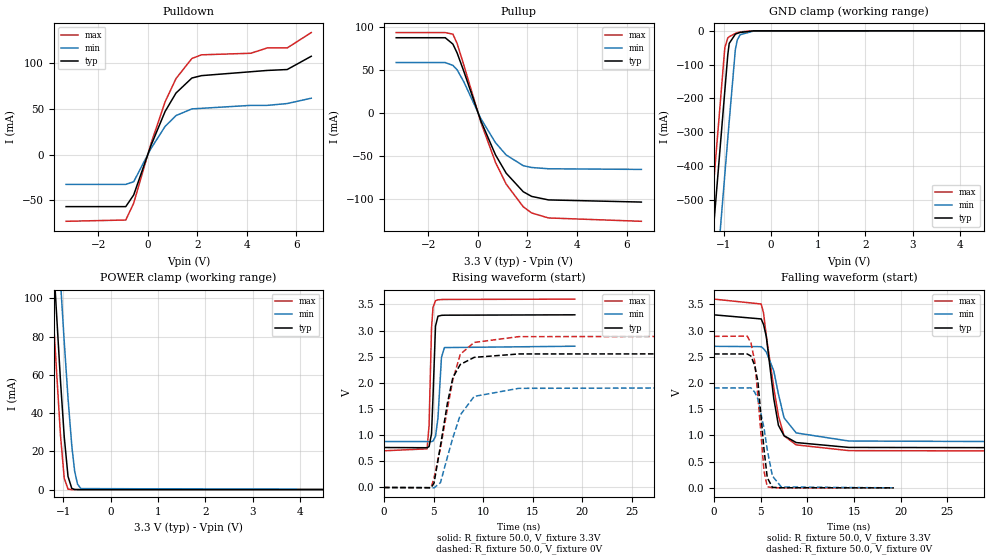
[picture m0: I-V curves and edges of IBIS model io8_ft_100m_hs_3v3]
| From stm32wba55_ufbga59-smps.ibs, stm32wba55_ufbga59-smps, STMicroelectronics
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[Model]   io8_ft_100m_hs_3v3
Model_type I/O
Polarity   Non-Inverting
Enable   Active-Low
| CAP_THRESHOLD on pad IOFT is "UDTCAPC" :
| Rising=30.0% of vddiom   Falling=70.0% of vddiom
| C_comp min and max val. don't necessarily correlate with the min and max pvt
| but are the smallest and greatest pad capacitance found.
| var   typ   min   max
C_comp   2.69710pF  2.55491pF  2.73102pF
|C_comp_pullup   1.75317pF  1.65278pF  1.79178pF
|C_comp_pulldown   943.93778fF  902.13346fF  939.24098fF
Vinl = 1.35V
Vinh = 1.8V
Vmeas = 1.65V   | Reference voltage for timing measurements
Cref  = 50.0pF   | Timing specification test load capacitance value
Rref  = 1.0MOhm   | Timing specification test load resistance value
Vref  = 1.815V   | Timing specification test load voltage
[Model Spec]
| TIME_THRESHOLD on pin ZIV11 is "CMOS" :
| Rising=50.0% of vdd   Falling=50.0% of vdd
Vinl 1.29050V 1.08150V 1.39050V
Vinh 1.79850V 1.49250V 1.94450V
| variable   typ   min   max
[Temperature Range] 25.0 140.0 -40.0
| variable   typ   min   max
[Voltage Range] 3.3V 2.7V 3.6V
| variable   typ   min   max
[POWER Clamp Reference] 3.3V 2.7V 3.6V
| variable   typ   min   max
[GND Clamp Reference] 0V 0V 0V
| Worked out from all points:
|   slope of the pulldown table from 0 to 0.495 V, typ, clamps not added: 14 ohm
|   slope of the pullup table from 0 to 0.495 V, typ, clamps not added: 13.8 ohm
|   GND clamp passes 1 mA (typ) near -0.51 V on its own axis
|   POWER clamp passes 1 mA (typ) near -0.83 V on its own axis
|   rising waveform, R_fixture 50.0, V_fixture 3.3V: 20-80 % time 250ps typ, 324ps min, 231ps max; typ from 0.764 V to 3.3 V
|   falling waveform, R_fixture 50.0, V_fixture 3.3V: 20-80 % time 1.12ns typ, 1.53ns min, 1.48ns max; typ from 3.3 V to 0.764 V
|   rising waveform, R_fixture 50.0, V_fixture 0V: 20-80 % time 1.41ns typ, 1.91ns min, 1.73ns max; typ from 0 V to 2.55 V
|   falling waveform, R_fixture 50.0, V_fixture 0V: 20-80 % time 784ps typ, 1.05ns min, 788ps max; typ from 2.55 V to 0 V
[POWER Clamp]
-3.3V     1.123A     1.139A     1.091A
-1.36V    189.2mA    238.8mA    158.1mA
-1.25V    139mA      190.3mA    108.1mA
-1.18V    107.9mA    159.9mA    77.22mA
-1.06V    57.23mA    109.3mA    28.68mA
-980mV    27.6mA     77.28mA    5.935mA
-900mV    6.895mA    47.74mA    242.8uA
-820mV    594.6uA    22.85mA    5.912uA
-760mV    69.41uA    9.714mA    358.6nA
-700mV    7.83uA     2.919mA    21.86nA
-630mV    611.5nA    529.9uA    954.5pA
6.6V      0A         0A         0A
[GND Clamp]
-3.3V     -4.134A    -4.382A    -4.006A
-1.59V    -1.227A    -1.475A    -1.099A
-1.25V    -648.9mA   -896.7mA   -520.9mA
-980mV    -189.9mA   -437.7mA   -61.92mA
-970mV    -172.9mA   -420.7mA   -48.45mA
-910mV    -70.86mA   -318.7mA   -21.03mA
-880mV    -37.23mA   -267.7mA   -17.31mA
-750mV    -9.908mA   -55.25mA   -7.768mA
-710mV    -7.626mA   -27.41mA   -5.608mA
-650mV    -4.885mA   -11.6mA    -3.058mA
-360mV    -31.22uA   -443.6uA   -1.188uA
6.6V      2.31nA     2.655uA    974.6pA
| variable   typ   min   max
[Pullup Reference] 3.3V 2.7V 3.6V
| variable   typ   min   max
[Pulldown Reference] 0V 0V 0V
[Pullup]
-3.3V     87.39mA    58.48mA    93.39mA
-1.32V    87.39mA    58.48mA    93.39mA
-1.01V    79.92mA    55.15mA    91.54mA
-840mV    69.62mA    50.05mA    80.64mA
-570mV    48.3mA     36.02mA    55.62mA
120mV     -9.566mA   -6.929mA   -11.25mA
710mV     -49.08mA   -34.92mA   -57.81mA
1.14V     -70.33mA   -49.14mA   -83.06mA
1.83V     -91.98mA   -61.62mA   -109.5mA
2.17V     -97.42mA   -63.75mA   -116.7mA
2.85V     -101.5mA   -65.23mA   -122.5mA
6.6V      -104mA     -65.97mA   -126.4mA
[Pulldown]
-3.3V     -56.7mA    -32.4mA    -72.73mA
-890mV    -56.7mA    -32.4mA    -71.32mA
-570mV    -43.94mA   -29.54mA   -52.99mA
120mV     9.474mA    6.407mA    11.48mA
700mV     47.33mA    30.97mA    57.88mA
1.14V     67.41mA    42.74mA    83.2mA
1.78V     83.75mA    50.04mA    105.1mA
2.17V     86.37mA    50.65mA    109.1mA
4.16V     90.61mA    53.89mA    110.8mA
4.82V     92.03mA    53.89mA    116.6mA
5.63V     93.04mA    55.89mA    116.6mA
6.6V      107.5mA    61.71mA    133.4mA
[Ramp]
dV/dt_r 1.53259V/1.41086ns 1.14345V/1.91029ns 1.73411V/1.72763ns
dV/dt_f 1.52157V/1.12298ns 1.09314V/1.46189ns 1.73924V/1.47498ns
R_load = 50.0
| Removed startup time: 0s 0s 0s  .
| Removed end time: 19.25ns.
[Rising Waveform]
R_fixture   = 50.0
V_fixture   = 3.3V
V_fixture_min = 2.7V
V_fixture_max = 3.6V
0s        764mV      878.1mV    701.3mV
4.35ns    759.8mV    877.9mV    738.6mV
4.55ns    782.3mV    876.5mV    1.182V
4.8ns     1.027V     876.1mV    3.05V
4.95ns    1.742V     888.7mV    3.445V
5.2ns     3.085V     975.1mV    3.57V
5.45ns    3.274V     1.331V     3.587V
5.8ns     3.29V      2.485V     3.592V
6.1ns     3.293V     2.674V     3.594V
19.25ns   3.3V       2.7V       3.6V
| Removed startup time: 0s 0s 0s  .
| Removed end time: 39.25ns.
[Falling Waveform]
R_fixture   = 50.0
V_fixture   = 3.3V
V_fixture_min = 2.7V
V_fixture_max = 3.6V
0s        3.3V       2.7V       3.6V
5.05ns    3.222V     2.693V     3.507V
5.3ns     3.116V     2.654V     3.338V
5.6ns     2.882V     2.59V      2.892V
6.4ns     1.699V     2.23V      1.904V
6.9ns     1.192V     1.787V     1.371V
7.5ns     994.9mV    1.336V     990.9mV
8.8ns     864.2mV    1.048V     820mV
14.45ns   771.2mV    893.3mV    710.1mV
39.25ns   764mV      878.1mV    701.3mV
| Removed startup time: 0s 0s 0s  .
| Removed end time: 39.2ns.
[Rising Waveform]
R_fixture   = 50.0
V_fixture   = 0V
V_fixture_min = 0V
V_fixture_max = 0V
0s        20.8nV     574.2nV    32.98nV
4.75ns    -4.717mV   -3.512mV   -3.576mV
5.05ns    82.95mV    -7.08mV    179.1mV
5.7ns     798.2mV    93.11mV    754mV
6.4ns     1.611V     580.7mV    1.504V
6.95ns    2.101V     950.8mV    2.057V
7.7ns     2.351V     1.387V     2.547V
9.1ns     2.487V     1.741V     2.772V
13.6ns    2.552V     1.895V     2.883V
39.2ns    2.554V     1.906V     2.89V
| Removed startup time: 0s 0s 0s  .
| Removed end time: 19.25ns.
[Falling Waveform]
R_fixture   = 50.0
V_fixture   = 0V
V_fixture_min = 0V
V_fixture_max = 0V
0s        2.554V     1.906V     2.89V
3.55ns    2.554V     1.906V     2.894V
3.95ns    2.514V     1.908V     2.767V
4.35ns    2.337V     1.827V     2.42V
4.7ns     2.022V     1.696V     1.743V
5.35ns    736.1mV    1.142V     322.4mV
5.7ns     195.4mV    725.2mV    20.86mV
6.25ns    10.28mV    227.4mV    3.246mV
7.2ns     2.221mV    17.74mV    1.646mV
19.25ns   27.12uV    32.82uV    48.95uV
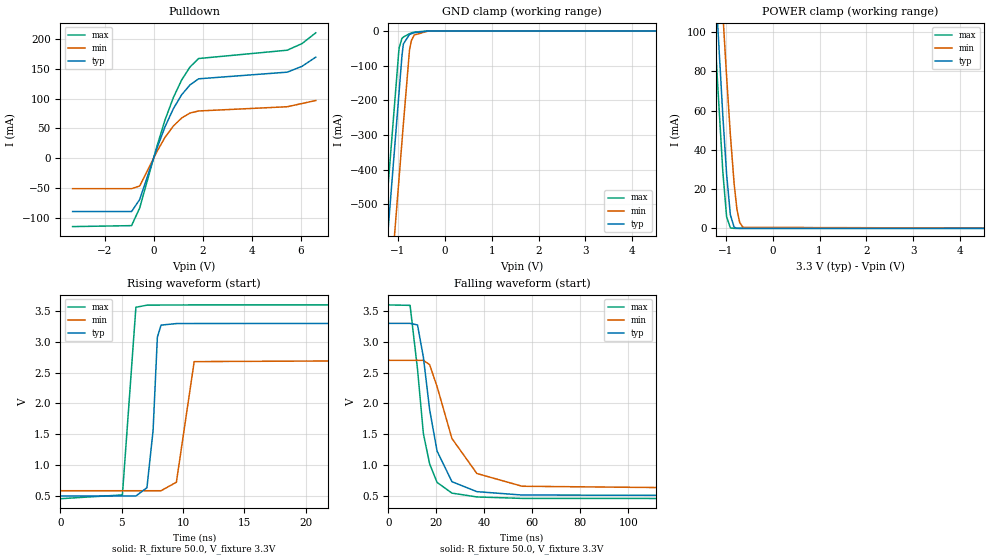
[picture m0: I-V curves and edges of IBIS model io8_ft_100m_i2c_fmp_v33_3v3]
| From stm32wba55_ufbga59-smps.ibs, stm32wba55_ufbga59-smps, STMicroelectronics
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[Model]   io8_ft_100m_i2c_fmp_v33_3v3
Model_type I/O_open_drain
Polarity   Non-Inverting
Enable   Active-Low
| CAP_THRESHOLD on pad IOFT is "UDTCAPC" :
| Rising=30.0% of vddiom   Falling=70.0% of vddiom
| C_comp min and max val. don't necessarily correlate with the min and max pvt
| but are the smallest and greatest pad capacitance found.
| var   typ   min   max
C_comp   2.70467pF  2.60096pF  2.73934pF
|C_comp_pulldown   2.70467pF  2.60096pF  2.73934pF
Vinl = 1.35V
Vinh = 1.8V
Vmeas = 1.65V   | Reference voltage for timing measurements
Cref  = 50.0pF   | Timing specification test load capacitance value
Rref  = 1.0MOhm   | Timing specification test load resistance value
Vref  = 1.815V   | Timing specification test load voltage
[Model Spec]
| TIME_THRESHOLD on pin ZII2CV11 is "CMOS" :
| Rising=50.0% of vdd   Falling=50.0% of vdd
Vinl 1.28450V 1.07650V 1.38450V
Vinh 1.79550V 1.49050V 1.94250V
| variable   typ   min   max
[Temperature Range] 25.0 140.0 -40.0
| variable   typ   min   max
[Voltage Range] 3.3V 2.7V 3.6V
| variable   typ   min   max
[POWER Clamp Reference] 3.3V 2.7V 3.6V
| variable   typ   min   max
[GND Clamp Reference] 0V 0V 0V
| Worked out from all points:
|   slope of the pulldown table from 0 to 0.495 V, typ, clamps not added: 8.84 ohm
|   GND clamp passes 1 mA (typ) near -0.51 V on its own axis
|   POWER clamp passes 1 mA (typ) near -0.83 V on its own axis
|   rising waveform, R_fixture 50.0, V_fixture 3.3V: 20-80 % time 550ps typ, 754ps min, 487ps max; typ from 0.496 V to 3.3 V
|   falling waveform, R_fixture 50.0, V_fixture 3.3V: 20-80 % time 7.24ns typ, 13.2ns min, 5.61ns max; typ from 3.3 V to 0.496 V
[POWER Clamp]
-3.3V     1.123A     1.139A     1.091A
-1.36V    189.2mA    238.8mA    158.1mA
-1.25V    139mA      190.3mA    108.1mA
-1.18V    107.9mA    159.9mA    77.22mA
-1.06V    57.23mA    109.3mA    28.68mA
-980mV    27.6mA     77.28mA    5.935mA
-900mV    6.895mA    47.74mA    242.8uA
-820mV    594.6uA    22.85mA    5.912uA
-760mV    69.41uA    9.714mA    358.6nA
-700mV    7.83uA     2.919mA    21.86nA
-630mV    611.5nA    529.9uA    954.5pA
6.6V      0A         0A         0A
[GND Clamp]
-3.3V     -4.134A    -4.382A    -4.006A
-1.59V    -1.227A    -1.475A    -1.099A
-1.25V    -648.9mA   -896.7mA   -520.9mA
-980mV    -189.9mA   -437.7mA   -61.92mA
-970mV    -172.9mA   -420.7mA   -48.45mA
-910mV    -70.86mA   -318.7mA   -21.03mA
-880mV    -37.23mA   -267.7mA   -17.31mA
-750mV    -9.908mA   -55.25mA   -7.768mA
-710mV    -7.626mA   -27.41mA   -5.608mA
-650mV    -4.885mA   -11.6mA    -3.058mA
-360mV    -31.22uA   -443.6uA   -1.188uA
6.6V      2.31nA     2.655uA    974.6pA
| variable   typ   min   max
[Pullup Reference] 3.3V 2.7V 3.6V
| variable   typ   min   max
[Pulldown Reference] 0V 0V 0V
[Pulldown]
-3.3V     -89.63mA   -51.21mA   -114.9mA
-900mV    -89.63mA   -51.21mA   -113.3mA
-570mV    -69.46mA   -46.7mA    -83.73mA
120mV     14.97mA    10.13mA    18.13mA
460mV     52.55mA    34.91mA    63.97mA
800mV     83.04mA    54mA       101.7mA
1.14V     106.6mA    67.57mA    131.5mA
1.48V     123.2mA    75.9mA     153.3mA
1.83V     133.4mA    79.37mA    167.5mA
5.44V     144.6mA    86.51mA    181.5mA
6.04V     154.4mA    91.91mA    192.6mA
6.6V      169.8mA    96.95mA    210.7mA
[Ramp]
dV/dt_r 1.68259V/549.39557ps 1.27116V/751.78769ps 1.88895V/488.49833ps
dV/dt_f 1.68262V/7.2351ns 1.27121V/13.13112ns 1.88896V/5.46778ns
R_load = 50.0
| Removed startup time: 0s 0s 0s  .
| Removed end time: 33.35ns.
[Rising Waveform]
R_fixture   = 50.0
V_fixture   = 3.3V
V_fixture_min = 2.7V
V_fixture_max = 3.6V
0s        495.6mV    581.3mV    451.7mV
5.05ns    495.6mV    581.3mV    512.9mV
6.15ns    495.6mV    581.3mV    3.562V
7.05ns    630.3mV    581.3mV    3.596V
7.55ns    1.56V      581.3mV    3.597V
7.9ns     3.077V     581.3mV    3.597V
8.2ns     3.272V     581.3mV    3.598V
9.45ns    3.297V     719.2mV    3.599V
10.9ns    3.298V     2.679V     3.6V
33.35ns   3.3V       2.7V       3.6V
| Removed startup time: 0s 0s 0s  .
| Removed end time: 248.4ns.
[Falling Waveform]
R_fixture   = 50.0
V_fixture   = 3.3V
V_fixture_min = 2.7V
V_fixture_max = 3.6V
0s        3.3V       2.7V       3.6V
9.05ns    3.3V       2.7V       3.593V
12.15ns   3.275V     2.7V       2.555V
14.6ns    2.75V      2.7V       1.508V
17.2ns    1.9V       2.629V     1.018V
20.3ns    1.226V     2.273V     716.5mV
26.5ns    728.3mV    1.429V     542.3mV
36.9ns    566.1mV    861.2mV    480.2mV
55.75ns   511.3mV    653.9mV    456.5mV
248.4ns   495.6mV    581.3mV    451.7mV
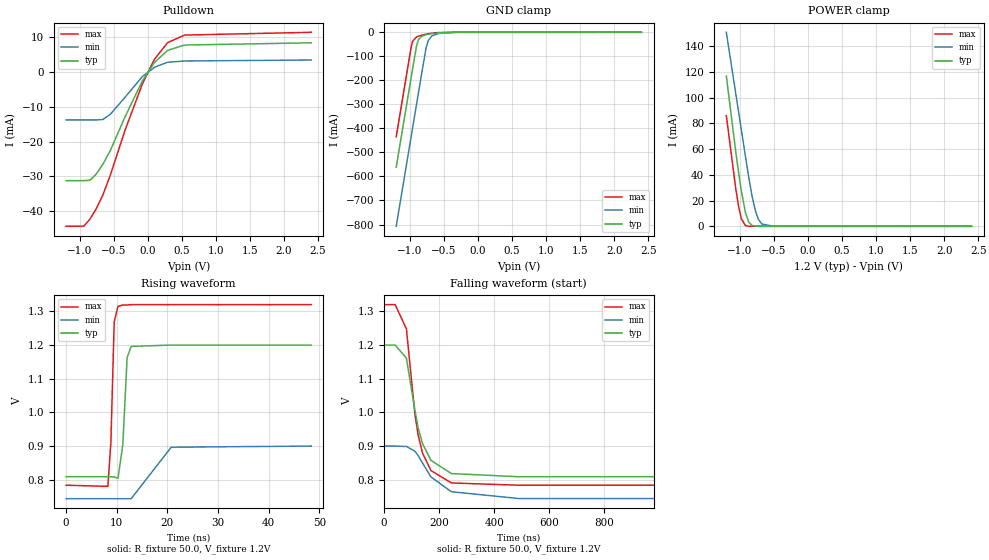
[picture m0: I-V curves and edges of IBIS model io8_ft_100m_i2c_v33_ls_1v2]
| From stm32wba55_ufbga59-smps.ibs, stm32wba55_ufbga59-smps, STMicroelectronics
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[Model]   io8_ft_100m_i2c_v33_ls_1v2
Model_type I/O_open_drain
Polarity   Non-Inverting
Enable   Active-Low
| CAP_THRESHOLD on pad IOFT is "UDTCAPC" :
| Rising=30.0% of vddiom   Falling=70.0% of vddiom
| C_comp min and max val. don't necessarily correlate with the min and max pvt
| but are the smallest and greatest pad capacitance found.
| var   typ   min   max
C_comp   1.75955pF  1.58205pF  1.89750pF
|C_comp_pulldown   1.75955pF  1.58205pF  1.89750pF
Vinl = 450.0mV
Vinh = 660.0mV
Vmeas = 600.0mV   | Reference voltage for timing measurements
Cref  = 50.0pF   | Timing specification test load capacitance value
Rref  = 1.0MOhm   | Timing specification test load resistance value
Vref  = 660.0mV   | Timing specification test load voltage
[Model Spec]
| TIME_THRESHOLD on pin ZII2CV11 is "CMOS" :
| Rising=50.0% of vdd   Falling=50.0% of vdd
Vinl 436.50000mV 342.50000mV 466.50000mV
Vinh 753.50000mV 549.50000mV 839.50000mV
| variable   typ   min   max
[Temperature Range] 25.0 140.0 -40.0
| variable   typ   min   max
[Voltage Range] 1.2V 900.0mV 1.32V
| variable   typ   min   max
[POWER Clamp Reference] 1.2V 900.0mV 1.32V
| variable   typ   min   max
[GND Clamp Reference] 0V 0V 0V
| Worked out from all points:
|   slope of the pulldown table from 0 to 0.18 V, typ, clamps not added: 40.6 ohm
|   GND clamp passes 1 mA (typ) near -0.51 V on its own axis
|   POWER clamp passes 1 mA (typ) near -0.83 V on its own axis
|   rising waveform, R_fixture 50.0, V_fixture 1.2V: 20-80 % time 743ps typ, 1.41ns min, 562ps max; typ from 0.809 V to 1.2 V
|   falling waveform, R_fixture 50.0, V_fixture 1.2V: 20-80 % time 59.4ns typ, 93.9ns min, 50.5ns max; typ from 1.2 V to 0.809 V
[POWER Clamp]
-1.2V     116.7mA    150.7mA    85.92mA
-1.06V    57.23mA    102.6mA    28.68mA
-1.02V    41.75mA    88.91mA    15.5mA
-980mV    27.6mA     75.18mA    5.935mA
-920mV    10.75mA    54.6mA     597.6uA
-870mV    3.065mA    37.68mA    60.82uA
-820mV    594.6uA    22.85mA    5.912uA
-770mV    99.71uA    11.47mA    572nA
-730mV    23.34uA    5.552mA    88.29nA
-680mV    3.779uA    1.833mA    8.565nA
-510mV    7.889nA    23.13uA    53.67pA
2.4V      0A         0A         0A
[GND Clamp]
-1.2V     -561.6mA   -807.5mA   -434.8mA
-980mV    -187.6mA   -433.5mA   -60.76mA
-960mV    -153.6mA   -399.5mA   -38.21mA
-900mV    -54.17mA   -297.5mA   -18.87mA
-870mV    -29.55mA   -246.5mA   -15.73mA
-830mV    -17.05mA   -178.5mA   -12.57mA
-760mV    -9.921mA   -62.77mA   -8.045mA
-730mV    -8.191mA   -35.56mA   -6.403mA
-680mV    -5.826mA   -15.57mA   -4.089mA
-580mV    -2.43mA    -5.043mA   -1.157mA
-330mV    -11.72uA   -245.5uA   -300.5nA
2.4V      872pA      1.056uA    338.3pA
| variable   typ   min   max
[Pullup Reference] 1.2V 900.0mV 1.32V
| variable   typ   min   max
[Pulldown Reference] 0V 0V 0V
[Pulldown]
-1.2V     -31.2mA    -13.81mA   -44.3mA
-940mV    -31.2mA    -13.81mA   -44.26mA
-850mV    -31.11mA   -13.81mA   -42.26mA
-760mV    -29.39mA   -13.81mA   -39.38mA
-660mV    -26.52mA   -13.68mA   -35.32mA
-550mV    -22.55mA   -12.17mA   -29.6mA
-330mV    -12.74mA   -7.204mA   -16.5mA
-80mV     -2.622mA   -1.37mA    -3.49mA
100mV     2.727mA    1.319mA    3.679mA
290mV     6.144mA    2.737mA    8.347mA
540mV     7.674mA    3.096mA    10.53mA
2.4V      8.312mA    3.389mA    11.33mA
[Ramp]
dV/dt_r 234.64946mV/730.32474ps 93.7375mV/1.38904ns 321.76547mV/556.33055ps
dV/dt_f 234.65958mV/57.74443ns 93.75738mV/89.13367ns 321.77283mV/49.68352ns
R_load = 50.0
| Removed startup time: 0s 0s 0s  .
| Removed end time: 48.4ns.
[Rising Waveform]
R_fixture   = 50.0
V_fixture   = 1.2V
V_fixture_min = 900.0mV
V_fixture_max = 1.32V
0s        808.9mV    743.7mV    783.7mV
8.25ns    808.9mV    743.7mV    780.3mV
8.85ns    808.9mV    743.7mV    912.1mV
9.5ns     808.4mV    743.7mV    1.269V
10.25ns   804.2mV    743.7mV    1.315V
11.2ns    903.5mV    743.7mV    1.319V
12.05ns   1.163V     743.7mV    1.319V
12.85ns   1.196V     743.7mV    1.32V
20.75ns   1.2V       896.6mV    1.32V
48.4ns    1.2V       900mV      1.32V
| Removed startup time: 0s 0s 0s  .
| Removed end time: 1.9984us.
[Falling Waveform]
R_fixture   = 50.0
V_fixture   = 1.2V
V_fixture_min = 900.0mV
V_fixture_max = 1.32V
0s        1.2V       900mV      1.32V
40.8ns    1.2V       900mV      1.32V
81.55ns   1.161V     898.8mV    1.248V
112.3ns   1.007V     884.6mV    994.5mV
124.5ns   952.6mV    871mV      931mV
140.3ns   906.8mV    849.2mV    878.6mV
170.6ns   857.5mV    808.3mV    827.2mV
244.7ns   818.3mV    764.3mV    790.4mV
489.4ns   808.9mV    744.2mV    783.7mV
1.998us   808.9mV    743.7mV    783.7mV
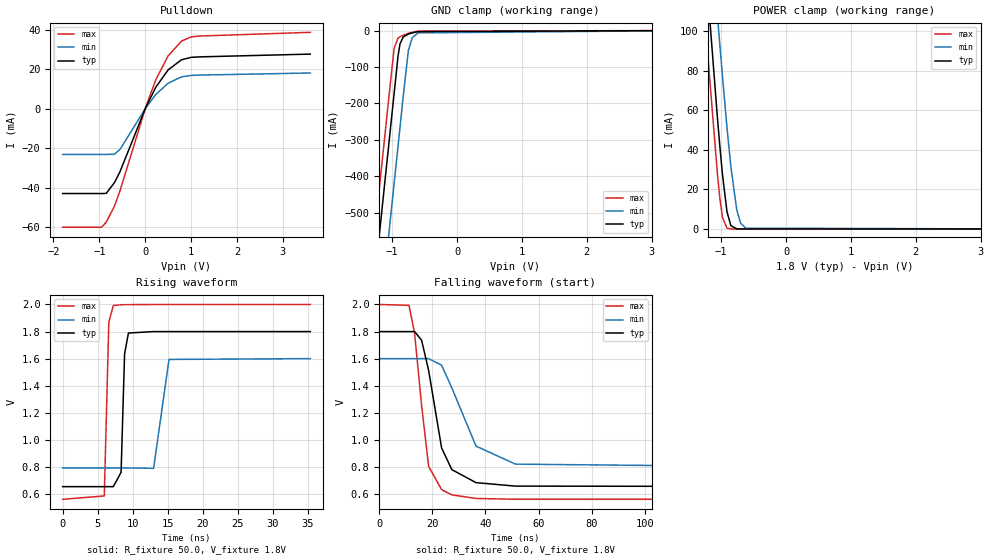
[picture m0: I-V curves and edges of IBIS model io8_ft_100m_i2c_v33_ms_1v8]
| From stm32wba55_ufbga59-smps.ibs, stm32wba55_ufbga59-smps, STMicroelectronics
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[Model]   io8_ft_100m_i2c_v33_ms_1v8
Model_type I/O_open_drain
Polarity   Non-Inverting
Enable   Active-Low
| CAP_THRESHOLD on pad IOFT is "UDTCAPC" :
| Rising=30.0% of vddiom   Falling=70.0% of vddiom
| C_comp min and max val. don't necessarily correlate with the min and max pvt
| but are the smallest and greatest pad capacitance found.
| var   typ   min   max
C_comp   2.22395pF  2.11500pF  2.41696pF
|C_comp_pulldown   2.22395pF  2.11500pF  2.41696pF
Vinl = 800.0mV
Vinh = 1.0V
Vmeas = 900.0mV   | Reference voltage for timing measurements
Cref  = 50.0pF   | Timing specification test load capacitance value
Rref  = 1.0MOhm   | Timing specification test load resistance value
Vref  = 990.0mV   | Timing specification test load voltage
[Model Spec]
| TIME_THRESHOLD on pin ZII2CV11 is "CMOS" :
| Rising=50.0% of vdd   Falling=50.0% of vdd
Vinl 697.50000mV 636.50000mV 765.50000mV
Vinh 1.08850V 942.50000mV 1.21750V
| variable   typ   min   max
[Temperature Range] 25.0 140.0 -40.0
| variable   typ   min   max
[Voltage Range] 1.8V 1.6V 2.0V
| variable   typ   min   max
[POWER Clamp Reference] 1.8V 1.6V 2.0V
| variable   typ   min   max
[GND Clamp Reference] 0V 0V 0V
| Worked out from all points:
|   slope of the pulldown table from 0 to 0.27 V, typ, clamps not added: 21.7 ohm
|   GND clamp passes 1 mA (typ) near -0.51 V on its own axis
|   POWER clamp passes 1 mA (typ) near -0.83 V on its own axis
|   rising waveform, R_fixture 50.0, V_fixture 1.8V: 20-80 % time 320ps typ, 505ps min, 244ps max; typ from 0.654 V to 1.8 V
|   falling waveform, R_fixture 50.0, V_fixture 1.8V: 20-80 % time 6.34ns typ, 10.2ns min, 4.35ns max; typ from 1.8 V to 0.654 V
[POWER Clamp]
-1.8V     396.4mA    438.1mA    365.5mA
-1.26V    143.5mA    194.6mA    112.6mA
-1.19V    112.3mA    164.2mA    81.56mA
-1.06V    57.23mA    109.3mA    28.68mA
-1.02V    41.75mA    93.06mA    15.5mA
-980mV    27.6mA     77.28mA    5.935mA
-910mV    8.693mA    51.24mA    382.3uA
-850mV    1.642mA    31.41mA    23.97uA
-760mV    69.41uA    9.714mA    358.6nA
-700mV    7.83uA     2.919mA    21.79nA
-620mV    424.6nA    410.3uA    573.9pA
3.6V      0A         0A         0A
[GND Clamp]
-1.8V     -1.583A    -1.83A     -1.456A
-1.43V    -953.9mA   -1.201A    -826.8mA
-1.24V    -630.9mA   -877.8mA   -503.8mA
-1.05V    -307.9mA   -554.8mA   -180.8mA
-970mV    -171.9mA   -418.8mA   -48.31mA
-910mV    -69.87mA   -316.8mA   -20.91mA
-880mV    -36.5mA    -265.8mA   -17.19mA
-830mV    -17.68mA   -180.8mA   -12.97mA
-750mV    -9.66mA    -53.66mA   -7.697mA
-690mV    -6.479mA   -19.19mA   -4.622mA
-600mV    -3.058mA   -6.478mA   -1.59mA
3.6V      1.281nA    1.39uA     517.2pA
| variable   typ   min   max
[Pullup Reference] 1.8V 1.6V 2.0V
| variable   typ   min   max
[Pulldown Reference] 0V 0V 0V
[Pulldown]
-1.8V     -42.97mA   -23.15mA   -59.99mA
-950mV    -42.97mA   -23.15mA   -59.99mA
-850mV    -42.87mA   -23.15mA   -57.45mA
-670mV    -37.41mA   -23.03mA   -49.3mA
-550mV    -31.91mA   -20.61mA   -41.6mA
10mV      539.8uA    356.7uA    722uA
230mV     10.88mA    7.174mA    14.64mA
500mV     19.69mA    12.93mA    26.79mA
790mV     24.78mA    16.15mA    34.26mA
1V        26.02mA    16.89mA    36.38mA
1.18V     26.27mA    17.05mA    36.82mA
3.6V      27.68mA    18.11mA    38.71mA
[Ramp]
dV/dt_r 687.66858mV/317.08277ps 484.89287mV/500.6144ps 863.98532mV/242.17746ps
dV/dt_f 687.6929mV/6.3296ns 484.93843mV/10.12648ns 864.00283mV/4.33716ns
R_load = 50.0
| Removed startup time: 0s 0s 0s  .
| Removed end time: 35.4ns.
[Rising Waveform]
R_fixture   = 50.0
V_fixture   = 1.8V
V_fixture_min = 1.6V
V_fixture_max = 2.0V
0s        653.8mV    791.8mV    560mV
5.95ns    653.8mV    791.8mV    585.2mV
6.6ns     653.8mV    791.8mV    1.871V
7.25ns    653.8mV    791.8mV    1.993V
8.35ns    760mV      791.8mV    1.998V
8.85ns    1.634V     791.8mV    1.999V
9.4ns     1.789V     791.8mV    1.999V
13ns      1.8V       789.2mV    2V
15.2ns    1.8V       1.594V     2V
35.4ns    1.8V       1.6V       2V
| Removed startup time: 0s 0s 0s  .
| Removed end time: 198.4ns.
[Falling Waveform]
R_fixture   = 50.0
V_fixture   = 1.8V
V_fixture_min = 1.6V
V_fixture_max = 2.0V
0s        1.8V       1.6V       2V
11.2ns    1.8V       1.6V       1.994V
13.3ns    1.8V       1.6V       1.791V
15.95ns   1.736V     1.6V       1.255V
18.6ns    1.513V     1.6V       803.8mV
23.5ns    939.1mV    1.551V     631.2mV
27.35ns   779.4mV    1.383V     593mV
36.45ns   683.4mV    953.3mV    566.4mV
51.3ns    657.7mV    820.2mV    560.4mV
198.4ns   653.8mV    791.8mV    560mV
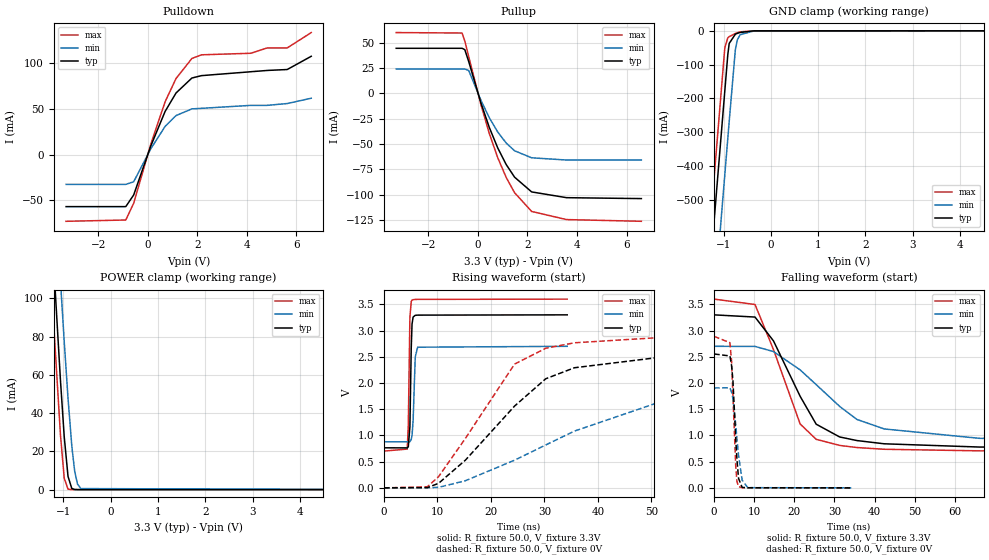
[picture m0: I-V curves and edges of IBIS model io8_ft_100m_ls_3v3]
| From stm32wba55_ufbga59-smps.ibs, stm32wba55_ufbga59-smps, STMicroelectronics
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[Model]   io8_ft_100m_ls_3v3
Model_type I/O
Polarity   Non-Inverting
Enable   Active-Low
| CAP_THRESHOLD on pad IOFT is "UDTCAPC" :
| Rising=30.0% of vddiom   Falling=70.0% of vddiom
| C_comp min and max val. don't necessarily correlate with the min and max pvt
| but are the smallest and greatest pad capacitance found.
| var   typ   min   max
C_comp   2.69649pF  2.55492pF  2.73022pF
|C_comp_pullup   1.75254pF  1.65210pF  1.79111pF
|C_comp_pulldown   943.95378fF  902.81846fF  939.11948fF
Vinl = 1.35V
Vinh = 1.8V
Vmeas = 1.65V   | Reference voltage for timing measurements
Cref  = 50.0pF   | Timing specification test load capacitance value
Rref  = 1.0MOhm   | Timing specification test load resistance value
Vref  = 1.815V   | Timing specification test load voltage
[Model Spec]
| TIME_THRESHOLD on pin ZIV11 is "CMOS" :
| Rising=50.0% of vdd   Falling=50.0% of vdd
Vinl 1.29050V 1.08150V 1.39050V
Vinh 1.79850V 1.49250V 1.94450V
| variable   typ   min   max
[Temperature Range] 25.0 140.0 -40.0
| variable   typ   min   max
[Voltage Range] 3.3V 2.7V 3.6V
| variable   typ   min   max
[POWER Clamp Reference] 3.3V 2.7V 3.6V
| variable   typ   min   max
[GND Clamp Reference] 0V 0V 0V
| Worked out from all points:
|   slope of the pulldown table from 0 to 0.495 V, typ, clamps not added: 14 ohm
|   slope of the pullup table from 0 to 0.495 V, typ, clamps not added: 13.8 ohm
|   GND clamp passes 1 mA (typ) near -0.51 V on its own axis
|   POWER clamp passes 1 mA (typ) near -0.83 V on its own axis
|   rising waveform, R_fixture 50.0, V_fixture 3.3V: 20-80 % time 256ps typ, 335ps min, 230ps max; typ from 0.764 V to 3.3 V
|   falling waveform, R_fixture 50.0, V_fixture 3.3V: 20-80 % time 10ns typ, 17.2ns min, 8.35ns max; typ from 3.3 V to 0.764 V
|   rising waveform, R_fixture 50.0, V_fixture 0V: 20-80 % time 14.7ns typ, 25.8ns min, 11.2ns max; typ from 0 V to 2.55 V
|   falling waveform, R_fixture 50.0, V_fixture 0V: 20-80 % time 1.02ns typ, 1.47ns min, 856ps max; typ from 2.55 V to 0 V
[POWER Clamp]
-3.3V     1.123A     1.139A     1.091A
-1.36V    189.2mA    238.8mA    158.1mA
-1.25V    139mA      190.3mA    108.1mA
-1.18V    107.9mA    159.9mA    77.22mA
-1.06V    57.23mA    109.3mA    28.68mA
-980mV    27.6mA     77.28mA    5.935mA
-900mV    6.895mA    47.74mA    242.8uA
-820mV    594.6uA    22.85mA    5.912uA
-760mV    69.41uA    9.714mA    358.6nA
-700mV    7.83uA     2.919mA    21.86nA
-630mV    611.5nA    529.9uA    954.5pA
6.6V      0A         0A         0A
[GND Clamp]
-3.3V     -4.134A    -4.382A    -4.006A
-1.59V    -1.227A    -1.475A    -1.099A
-1.25V    -648.9mA   -896.7mA   -520.9mA
-980mV    -189.9mA   -437.7mA   -61.92mA
-970mV    -172.9mA   -420.7mA   -48.45mA
-910mV    -70.86mA   -318.7mA   -21.03mA
-880mV    -37.23mA   -267.7mA   -17.31mA
-750mV    -9.908mA   -55.25mA   -7.768mA
-710mV    -7.626mA   -27.41mA   -5.608mA
-650mV    -4.885mA   -11.6mA    -3.058mA
-360mV    -31.22uA   -443.6uA   -1.188uA
6.6V      2.31nA     2.655uA    974.6pA
| variable   typ   min   max
[Pullup Reference] 3.3V 2.7V 3.6V
| variable   typ   min   max
[Pulldown Reference] 0V 0V 0V
[Pullup]
-3.3V     44.28mA    23.87mA    59.8mA
-640mV    44.28mA    23.87mA    59.35mA
-530mV    42.98mA    23.87mA    51.44mA
-370mV    31.03mA    22.28mA    35.9mA
120mV     -9.566mA   -6.929mA   -11.25mA
460mV     -33.84mA   -24.28mA   -39.82mA
800mV     -54.04mA   -38.32mA   -63.68mA
1.14V     -70.33mA   -49.14mA   -83.06mA
1.48V     -82.86mA   -56.83mA   -98.19mA
2.17V     -97.42mA   -63.75mA   -116.7mA
3.58V     -103.1mA   -65.97mA   -124.7mA
6.6V      -104mA     -65.97mA   -126.4mA
[Pulldown]
-3.3V     -56.7mA    -32.4mA    -72.73mA
-890mV    -56.7mA    -32.4mA    -71.32mA
-570mV    -43.94mA   -29.54mA   -52.99mA
120mV     9.474mA    6.407mA    11.48mA
700mV     47.33mA    30.97mA    57.88mA
1.14V     67.41mA    42.74mA    83.2mA
1.78V     83.75mA    50.04mA    105.1mA
2.17V     86.37mA    50.65mA    109.1mA
4.16V     90.61mA    53.89mA    110.8mA
4.82V     92.03mA    53.89mA    116.6mA
5.63V     93.04mA    55.89mA    116.6mA
6.6V      107.5mA    61.71mA    133.4mA
[Ramp]
dV/dt_r 1.53259V/14.59259ns 1.14353V/25.6011ns 1.73412V/11.03587ns
dV/dt_f 1.52158V/9.99296ns 1.09316V/17.14573ns 1.73923V/7.98999ns
R_load = 50.0
| Removed startup time: 0s 0s 0s  .
| Removed end time: 34.25ns.
[Rising Waveform]
R_fixture   = 50.0
V_fixture   = 3.3V
V_fixture_min = 2.7V
V_fixture_max = 3.6V
0s        764mV      878.1mV    701.3mV
4.35ns    762.3mV    877.9mV    739.8mV
4.55ns    784mV      877.1mV    1.18V
4.85ns    1.167V     881mV      3.256V
5.1ns     2.666V     923.7mV    3.554V
5.25ns    3.124V     996.7mV    3.581V
5.45ns    3.258V     1.281V     3.59V
5.85ns    3.291V     2.496V     3.594V
6.3ns     3.295V     2.683V     3.595V
34.25ns   3.3V       2.7V       3.6V
| Removed startup time: 0s 0s 0s  .
| Removed end time: 249.25ns.
[Falling Waveform]
R_fixture   = 50.0
V_fixture   = 3.3V
V_fixture_min = 2.7V
V_fixture_max = 3.6V
0s        3.3V       2.7V       3.6V
10.2ns    3.258V     2.698V     3.498V
14.8ns    2.804V     2.6V       2.639V
21.45ns   1.746V     2.25V      1.219V
25.45ns   1.214V     1.969V     926mV
31.3ns    970.9mV    1.554V     809.6mV
35.6ns    902.3mV    1.305V     769.1mV
42.4ns    840.6mV    1.124V     736.1mV
66.15ns   778.6mV    944.6mV    706.1mV
249.3ns   764mV      878.1mV    701.3mV
| Removed startup time: 0s 0s 0s  .
| Removed end time: 249.25ns.
[Rising Waveform]
R_fixture   = 50.0
V_fixture   = 0V
V_fixture_min = 0V
V_fixture_max = 0V
0s        20.8nV     574.2nV    32.98nV
8.1ns     4.365mV    258.1uV    19.62mV
10.2ns    85.96mV    9.641mV    212.1mV
15.2ns    526.1mV    135.6mV    940.2mV
24.4ns    1.559V     527.2mV    2.36V
30.25ns   2.082V     819mV      2.663V
35.6ns    2.291V     1.083V     2.767V
50.9ns    2.482V     1.615V     2.863V
73.85ns   2.541V     1.824V     2.887V
249.3ns   2.554V     1.906V     2.89V
| Removed startup time: 0s 0s 0s  .
| Removed end time: 34.2ns.
[Falling Waveform]
R_fixture   = 50.0
V_fixture   = 0V
V_fixture_min = 0V
V_fixture_max = 0V
0s        2.554V     1.906V     2.89V
3.95ns    2.516V     1.909V     2.769V
4.35ns    2.34V      1.829V     2.424V
4.7ns     2.052V     1.701V     1.767V
5.4ns     927mV      1.202V     408.6mV
5.7ns     539.6mV    933.5mV    124.7mV
6.1ns     180mV      617.8mV    24.47mV
7ns       8.146mV    147.6mV    3.732mV
8.4ns     2.338mV    3.942mV    2.184mV
34.2ns    159.7uV    209.6uV    133.6uV
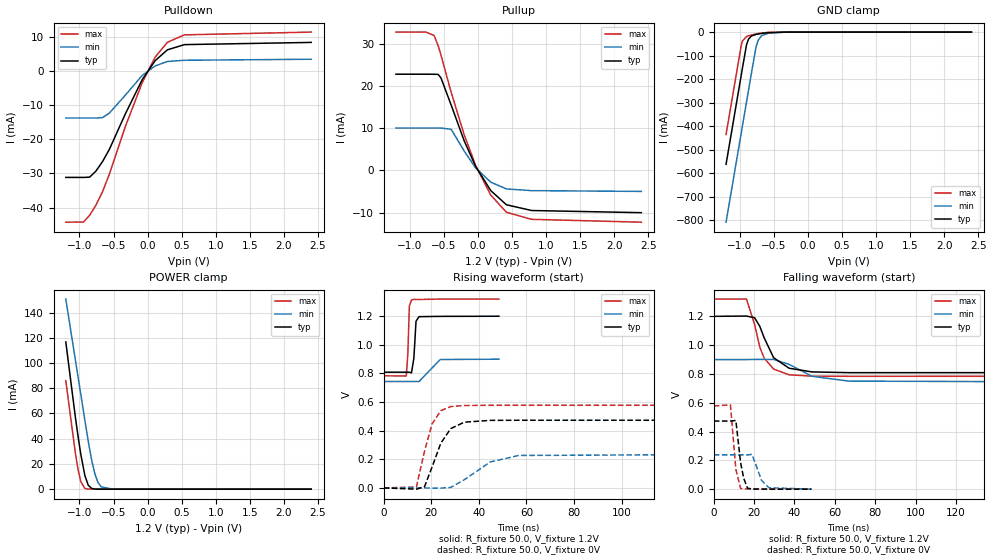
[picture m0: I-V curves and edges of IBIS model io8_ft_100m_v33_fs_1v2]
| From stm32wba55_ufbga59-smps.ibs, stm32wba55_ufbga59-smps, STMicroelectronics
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[Model]   io8_ft_100m_v33_fs_1v2
Model_type I/O
Polarity   Non-Inverting
Enable   Active-Low
| CAP_THRESHOLD on pad IOFT is "UDTCAPC" :
| Rising=30.0% of vddiom   Falling=70.0% of vddiom
| C_comp min and max val. don't necessarily correlate with the min and max pvt
| but are the smallest and greatest pad capacitance found.
| var   typ   min   max
C_comp   1.83455pF  1.64923pF  1.97629pF
|C_comp_pullup   1.12510pF  1.02590pF  1.16105pF
|C_comp_pulldown   709.45000fF  623.32501fF  815.23500fF
Vinl = 450.0mV
Vinh = 660.0mV
Vmeas = 600.0mV   | Reference voltage for timing measurements
Cref  = 50.0pF   | Timing specification test load capacitance value
Rref  = 1.0MOhm   | Timing specification test load resistance value
Vref  = 660.0mV   | Timing specification test load voltage
[Model Spec]
| TIME_THRESHOLD on pin ZIV33M is "CMOS" :
| Rising=50.0% of vddiom   Falling=50.0% of vddiom
Vinl 436.50000mV 342.50000mV 466.50000mV
Vinh 753.50000mV 549.50000mV 839.50000mV
| variable   typ   min   max
[Temperature Range] 25.0 140.0 -40.0
| variable   typ   min   max
[Voltage Range] 1.2V 900.0mV 1.32V
| variable   typ   min   max
[POWER Clamp Reference] 1.2V 900.0mV 1.32V
| variable   typ   min   max
[GND Clamp Reference] 0V 0V 0V
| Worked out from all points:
|   slope of the pulldown table from 0 to 0.18 V, typ, clamps not added: 40.6 ohm
|   slope of the pullup table from 0 to 0.18 V, typ, clamps not added: 39.4 ohm
|   GND clamp passes 1 mA (typ) near -0.51 V on its own axis
|   POWER clamp passes 1 mA (typ) near -0.83 V on its own axis
|   rising waveform, R_fixture 50.0, V_fixture 1.2V: 20-80 % time 850ps typ, 1.54ns min, 594ps max; typ from 0.809 V to 1.2 V
|   falling waveform, R_fixture 50.0, V_fixture 1.2V: 20-80 % time 8.36ns typ, 14.3ns min, 6.93ns max; typ from 1.2 V to 0.809 V
|   rising waveform, R_fixture 50.0, V_fixture 0V: 20-80 % time 7.01ns typ, 13.1ns min, 5.37ns max; typ from 0 V to 0.473 V
|   falling waveform, R_fixture 50.0, V_fixture 0V: 20-80 % time 2.69ns typ, 4.09ns min, 2.23ns max; typ from 0.473 V to 0 V
[POWER Clamp]
-1.2V     116.7mA    150.7mA    85.92mA
-1.06V    57.23mA    102.6mA    28.68mA
-1.02V    41.75mA    88.91mA    15.5mA
-980mV    27.6mA     75.18mA    5.935mA
-920mV    10.75mA    54.6mA     597.6uA
-870mV    3.065mA    37.68mA    60.82uA
-820mV    594.6uA    22.85mA    5.912uA
-770mV    99.71uA    11.47mA    572nA
-730mV    23.34uA    5.552mA    88.29nA
-680mV    3.779uA    1.833mA    8.565nA
-510mV    7.889nA    23.13uA    53.67pA
2.4V      0A         0A         0A
[GND Clamp]
-1.2V     -561.6mA   -807.5mA   -434.8mA
-980mV    -187.6mA   -433.5mA   -60.76mA
-960mV    -153.6mA   -399.5mA   -38.21mA
-900mV    -54.17mA   -297.5mA   -18.87mA
-870mV    -29.55mA   -246.5mA   -15.73mA
-830mV    -17.05mA   -178.5mA   -12.57mA
-760mV    -9.921mA   -62.77mA   -8.045mA
-730mV    -8.191mA   -35.56mA   -6.403mA
-680mV    -5.826mA   -15.57mA   -4.089mA
-580mV    -2.43mA    -5.043mA   -1.157mA
-330mV    -11.72uA   -245.5uA   -300.5nA
2.4V      872pA      1.055uA    338.3pA
| variable   typ   min   max
[Pullup Reference] 1.2V 900.0mV 1.32V
| variable   typ   min   max
[Pulldown Reference] 0V 0V 0V
[Pullup]
-1.2V     22.83mA    10.05mA    32.83mA
-760mV    22.83mA    10.05mA    32.83mA
-640mV    22.82mA    10.05mA    32.02mA
-580mV    22.78mA    10.05mA    29.58mA
-540mV    21.98mA    10.05mA    27.42mA
-390mV    15.52mA    9.759mA    18.55mA
-200mV    7.069mA    4.63mA     8.528mA
-30mV     926.7uA    571.2uA    1.132mA
190mV     -4.777mA   -2.782mA   -5.837mA
420mV     -8.158mA   -4.403mA   -9.943mA
790mV     -9.528mA   -4.812mA   -11.62mA
2.4V      -10.04mA   -4.994mA   -12.3mA
[Pulldown]
-1.2V     -31.2mA    -13.81mA   -44.3mA
-940mV    -31.2mA    -13.81mA   -44.26mA
-850mV    -31.11mA   -13.81mA   -42.26mA
-760mV    -29.39mA   -13.81mA   -39.38mA
-660mV    -26.52mA   -13.68mA   -35.32mA
-560mV    -22.95mA   -12.35mA   -30.17mA
-330mV    -12.74mA   -7.204mA   -16.5mA
-80mV     -2.622mA   -1.37mA    -3.49mA
110mV     2.963mA    1.428mA    3.999mA
290mV     6.144mA    2.737mA    8.347mA
540mV     7.674mA    3.096mA    10.53mA
2.4V      8.319mA    3.393mA    11.34mA
[Ramp]
dV/dt_r 283.7949mV/6.92861ns 142.77217mV/13.00756ns 346.61957mV/5.26294ns
dV/dt_f 234.65831mV/8.2768ns 93.77056mV/13.83837ns 321.77305mV/6.57592ns
R_load = 50.0
| Removed startup time: 0s 0s 0s  .
| Removed end time: 48.4ns.
[Rising Waveform]
R_fixture   = 50.0
V_fixture   = 1.2V
V_fixture_min = 900.0mV
V_fixture_max = 1.32V
0s        808.9mV    743.7mV    783.7mV
9.5ns     808.9mV    743.7mV    782.2mV
10.15ns   809mV      743.7mV    932.1mV
10.8ns    808.5mV    743.7mV    1.272V
11.7ns    804.5mV    743.7mV    1.314V
12.7ns    907.6mV    743.7mV    1.318V
13.6ns    1.165V     743.7mV    1.317V
14.85ns   1.197V     743.7mV    1.317V
23.75ns   1.199V     897.3mV    1.32V
48.4ns    1.2V       899.8mV    1.32V
| Removed startup time: 0s 0s 0s  .
| Removed end time: 198.4ns.
[Falling Waveform]
R_fixture   = 50.0
V_fixture   = 1.2V
V_fixture_min = 900.0mV
V_fixture_max = 1.32V
0s        1.2V       900mV      1.32V
16.2ns    1.202V     900mV      1.32V
20.25ns   1.19V      900.9mV    1.143V
22.8ns    1.131V     901mV      986.3mV
24.95ns   1.052V     900.6mV    910.1mV
29.65ns   912.7mV    900.7mV    833.9mV
37.35ns   839.7mV    866.5mV    794.1mV
48.6ns    814.2mV    784.1mV    784.7mV
66.9ns    809mV      750.4mV    783.6mV
198.4ns   808.9mV    743.7mV    783.7mV
| Removed startup time: 0s 0s 0s  .
| Removed end time: 198.4ns.
[Rising Waveform]
R_fixture   = 50.0
V_fixture   = 0V
V_fixture_min = 0V
V_fixture_max = 0V
0s        4.84nV     985.4nV    4.25nV
13.75ns   -8.794mV   2.88uV     6.54mV
17.15ns   8.066mV    14.11uV    255.9mV
20.35ns   146.8mV    -1.516mV   448.2mV
24ns      312.2mV    -1.26mV    539.4mV
28.15ns   414.1mV    3.481mV    568.6mV
33.85ns   459.4mV    56.82mV    576.2mV
44.8ns    472.1mV    181.5mV    577.5mV
56.7ns    472.8mV    226.7mV    577.6mV
198.4ns   473mV      238mV      577.7mV
| Removed startup time: 0s 0s 0s  .
| Removed end time: 48.4ns.
[Falling Waveform]
R_fixture   = 50.0
V_fixture   = 0V
V_fixture_min = 0V
V_fixture_max = 0V
0s        473mV      238mV      577.7mV
8.25ns    473mV      238mV      585.4mV
10.95ns   476.8mV    238mV      137.2mV
13.3ns    182.9mV    238mV      5.301mV
14.85ns   74.75mV    238mV      2.102mV
16.75ns   6.244mV    238mV      1.661mV
18.95ns   1.574mV    241.8mV    836.5uV
23.7ns    581.5uV    60.1mV     261uV
27.3ns    294uV      10.06mV    130.8uV
48.4ns    10.52uV    152.8uV    501.6nV
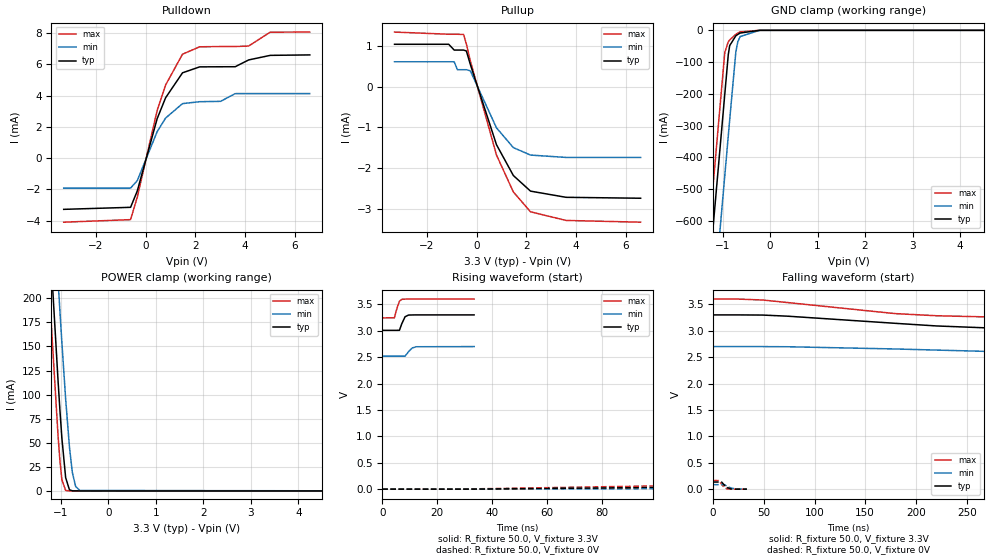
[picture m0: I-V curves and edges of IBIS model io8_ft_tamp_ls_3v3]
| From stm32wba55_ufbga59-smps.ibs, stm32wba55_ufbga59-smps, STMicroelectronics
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[Model]   io8_ft_tamp_ls_3v3
Model_type I/O
Polarity   Non-Inverting
Enable   Active-Low
| CAP_THRESHOLD on pad IOFT is "UDTCAPC" :
| Rising=30.0% of vddiom   Falling=70.0% of vddiom
| C_comp min and max val. don't necessarily correlate with the min and max pvt
| but are the smallest and greatest pad capacitance found.
| var   typ   min   max
C_comp   8.02941pF  7.67208pF  8.31249pF
|C_comp_pullup   5.44700pF  5.17570pF  5.56484pF
|C_comp_pulldown   2.58241pF  2.49637pF  2.74765pF
Vinl = 1.35V
Vinh = 1.8V
Vmeas = 1.65V   | Reference voltage for timing measurements
Cref  = 50.0pF   | Timing specification test load capacitance value
Rref  = 1.0MOhm   | Timing specification test load resistance value
Vref  = 1.815V   | Timing specification test load voltage
[Model Spec]
| TIME_THRESHOLD on pin ZIV33SW is "CMOS" :
| Rising=50.0% of VDDV33SW   Falling=50.0% of VDDV33SW
Vinl 1.28450V 1.07650V 1.38450V
Vinh 1.79550V 1.49050V 1.94250V
| variable   typ   min   max
[Temperature Range] 25.0 140.0 -40.0
| variable   typ   min   max
[Voltage Range] 3.3V 2.7V 3.6V
| variable   typ   min   max
[POWER Clamp Reference] 3.3V 2.7V 3.6V
| variable   typ   min   max
[GND Clamp Reference] 0V 0V 0V
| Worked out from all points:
|   slope of the pulldown table from 0 to 0.495 V, typ, clamps not added: 186 ohm
|   slope of the pullup table from 0 to 0.495 V, typ, clamps not added: 521 ohm
|   GND clamp passes 1 mA (typ) near -0.47 V on its own axis
|   POWER clamp passes 1 mA (typ) near -0.81 V on its own axis
|   rising waveform, R_fixture 50.0, V_fixture 3.3V: 20-80 % time 1.31ns typ, 1.64ns min, 1.18ns max; typ from 3.01 V to 3.3 V
|   falling waveform, R_fixture 50.0, V_fixture 3.3V: 20-80 % time 147ns typ, 227ns min, 112ns max; typ from 3.3 V to 3.01 V
|   rising waveform, R_fixture 50.0, V_fixture 0V: 20-80 % time 172ns typ, 297ns min, 124ns max; typ from 0 V to 0.135 V
|   falling waveform, R_fixture 50.0, V_fixture 0V: 20-80 % time 4.71ns typ, 6.26ns min, 4.14ns max; typ from 0.135 V to 0 V
[POWER Clamp]
-3.3V     2.246A     2.279A     2.182A
-1.26V    287mA      389.3mA    225.1mA
-1.19V    224.6mA    328.4mA    163.1mA
-1.06V    114.5mA    218.6mA    57.35mA
-1.02V    83.5mA     186.1mA    30.99mA
-980mV    55.21mA    154.6mA    11.87mA
-900mV    13.79mA    95.47mA    485.6uA
-820mV    1.189mA    45.7mA     11.82uA
-760mV    138.8uA    19.43mA    717.3nA
-690mV    10.88uA    4.64mA     27.56nA
-600mV    410.2nA    489.5uA    725pA
6.6V      0A         0A         0A
[GND Clamp]
-3.3V     -4.191A    -4.447A    -4.059A
-1.59V    -1.284A    -1.54A     -1.152A
-1.25V    -705.7mA   -962.2mA   -574mA
-960mV    -212.7mA   -469.2mA   -81mA
-950mV    -195.7mA   -452.2mA   -68.07mA
-880mV    -77.2mA    -333.2mA   -36.04mA
-850mV    -48.09mA   -282.2mA   -30.39mA
-720mV    -17.06mA   -67.51mA   -12.51mA
-680mV    -12.85mA   -36.48mA   -8.6mA
-630mV    -8.529mA   -19.6mA    -4.86mA
-220mV    -490.4nA   -42.83uA   -18.74nA
6.6V      5.835nA    6.044uA    3.958nA
| variable   typ   min   max
[Pullup Reference] 3.3V 2.7V 3.6V
| variable   typ   min   max
[Pulldown Reference] 0V 0V 0V
[Pullup]
-3.3V     1.045mA    615.3uA    1.345mA
-1.12V    1.045mA    615.3uA    1.292mA
-900mV    902.7uA    615.2uA    1.292mA
-770mV    902.7uA    420uA      1.292mA
-520mV    902.7uA    419.7uA    1.286mA
-410mV    880uA      419.7uA    1.048mA
-250mV    548.2uA    390.8uA    636.9uA
800mV     -1.423mA   -1.009mA   -1.677mA
1.48V     -2.183mA   -1.497mA   -2.587mA
2.17V     -2.567mA   -1.68mA    -3.075mA
3.6V      -2.719mA   -1.738mA   -3.288mA
6.6V      -2.742mA   -1.738mA   -3.331mA
[Pulldown]
-3.3V     -3.274mA   -1.916mA   -4.095mA
-610mV    -3.144mA   -1.916mA   -3.932mA
-340mV    -2.099mA   -1.437mA   -2.495mA
460mV     2.524mA    1.696mA    3.053mA
800mV     3.862mA    2.563mA    4.678mA
1.48V     5.456mA    3.486mA    6.647mA
2.17V     5.835mA    3.609mA    7.118mA
3.01V     5.842mA    3.631mA    7.135mA
3.6V      5.844mA    4.125mA    7.136mA
4.14V     6.279mA    4.125mA    7.167mA
5.01V     6.571mA    4.125mA    8.056mA
6.6V      6.6mA      4.125mA    8.059mA
[Ramp]
dV/dt_r 80.90622mV/171.52622ns 51.26253mV/296.53668ns 98.34735mV/123.05983ns
dV/dt_f 175.29321mV/146.71447ns 108.34721mV/225.77344ns 214.11029mV/111.7005ns
R_load = 50.0
| Removed startup time: 0s 0s 0s  .
| Removed end time: 33.4ns.
[Rising Waveform]
R_fixture   = 50.0
V_fixture   = 3.3V
V_fixture_min = 2.7V
V_fixture_max = 3.6V
0s        3.008V     2.519V     3.243V
4.4ns     3.008V     2.519V     3.245V
5.45ns    3.008V     2.519V     3.442V
6.25ns    3.009V     2.519V     3.558V
7.1ns     3.131V     2.519V     3.595V
8.3ns     3.265V     2.519V     3.599V
9.55ns    3.297V     2.603V     3.6V
10.9ns    3.299V     2.673V     3.6V
12.3ns    3.3V       2.697V     3.6V
33.4ns    3.3V       2.7V       3.6V
| Removed startup time: 0s 0s 0s  .
| Removed end time: 1.1984us.
[Falling Waveform]
R_fixture   = 50.0
V_fixture   = 3.3V
V_fixture_min = 2.7V
V_fixture_max = 3.6V
0s        3.3V       2.7V       3.6V
24.45ns   3.3V       2.7V       3.6V
48.9ns    3.297V     2.7V       3.582V
73.35ns   3.276V     2.697V     3.534V
179.3ns   3.141V     2.655V     3.325V
220.1ns   3.091V     2.634V     3.284V
281ns     3.046V     2.603V     3.257V
391.4ns   3.017V     2.555V     3.245V
538.1ns   3.009V     2.529V     3.243V
1.198us   3.008V     2.519V     3.243V
| Removed startup time: 0s 0s 0s  .
| Removed end time: 1.19835us.
[Rising Waveform]
R_fixture   = 50.0
V_fixture   = 0V
V_fixture_min = 0V
V_fixture_max = 0V
0s        162.8nV    4.5uV      290.6nV
25.45ns   27.33uV    -6.04uV    865.3uV
34.4ns    1.193mV    72.63uV    6.742mV
154.4ns   58.94mV    16.92mV    108.5mV
179.8ns   71.68mV    21.69mV    125.8mV
219ns     91.2mV     29.1mV     143mV
272.1ns   110.1mV    39.05mV    154.9mV
375.4ns   127.4mV    57.9mV     162.1mV
577ns     134.1mV    78.15mV    163.9mV
1.198us   134.8mV    85.44mV    163.9mV
| Removed startup time: 0s 0s 0s  .
| Removed end time: 33.35ns.
[Falling Waveform]
R_fixture   = 50.0
V_fixture   = 0V
V_fixture_min = 0V
V_fixture_max = 0V
0s        134.9mV    85.49mV    163.9mV
5.9ns     134.9mV    85.49mV    162.7mV
6.8ns     134.9mV    85.49mV    140.9mV
8.3ns     134.7mV    85.49mV    93.42mV
8.85ns    127mV      85.49mV    79.75mV
11.25ns   71.72mV    84.49mV    32.66mV
13.9ns    32.45mV    53.53mV    3.9mV
17.4ns    3.735mV    25.61mV    281.9uV
21.8ns    192.5uV    5.908mV    46.04uV
33.35ns   13.19uV    42.12uV    23.13uV
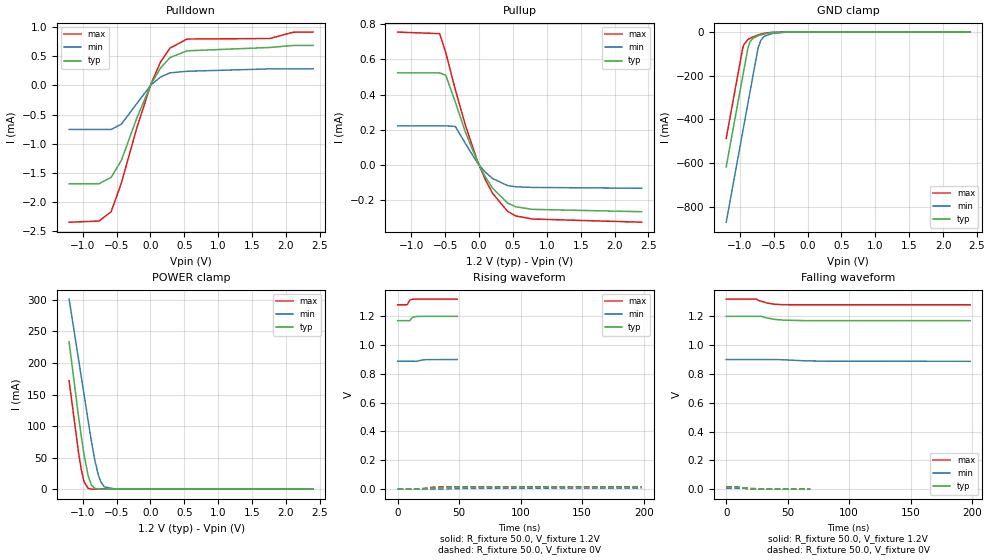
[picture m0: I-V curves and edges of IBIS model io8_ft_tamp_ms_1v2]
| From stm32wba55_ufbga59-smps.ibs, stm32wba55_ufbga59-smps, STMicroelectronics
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[Model]   io8_ft_tamp_ms_1v2
Model_type I/O
Polarity   Non-Inverting
Enable   Active-Low
| CAP_THRESHOLD on pad IOFT is "UDTCAPC" :
| Rising=30.0% of vddiom   Falling=70.0% of vddiom
| C_comp min and max val. don't necessarily correlate with the min and max pvt
| but are the smallest and greatest pad capacitance found.
| var   typ   min   max
C_comp   4.69898pF  4.28274pF  4.82427pF
|C_comp_pullup   2.96080pF  2.69780pF  2.96533pF
|C_comp_pulldown   1.73819pF  1.58493pF  1.85895pF
Vinl = 450.0mV
Vinh = 660.0mV
Vmeas = 600.0mV   | Reference voltage for timing measurements
Cref  = 50.0pF   | Timing specification test load capacitance value
Rref  = 1.0MOhm   | Timing specification test load resistance value
Vref  = 660.0mV   | Timing specification test load voltage
[Model Spec]
| TIME_THRESHOLD on pin ZIV33SW is "CMOS" :
| Rising=50.0% of VDDV33SW   Falling=50.0% of VDDV33SW
Vinl 436.50000mV 342.50000mV 466.50000mV
Vinh 753.50000mV 549.50000mV 839.50000mV
| variable   typ   min   max
[Temperature Range] 25.0 140.0 -40.0
| variable   typ   min   max
[Voltage Range] 1.2V 900.0mV 1.32V
| variable   typ   min   max
[POWER Clamp Reference] 1.2V 900.0mV 1.32V
| variable   typ   min   max
[GND Clamp Reference] 0V 0V 0V
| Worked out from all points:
|   slope of the pulldown table from 0 to 0.18 V, typ, clamps not added: 517 ohm
|   slope of the pullup table from 0 to 0.18 V, typ, clamps not added: 1.49 kohm
|   GND clamp passes 1 mA (typ) near -0.47 V on its own axis
|   POWER clamp passes 1 mA (typ) near -0.81 V on its own axis
[POWER Clamp]
-1.2V     233.4mA    301.3mA    171.8mA
-1.06V    114.5mA    205.3mA    57.35mA
-1.02V    83.5mA     177.8mA    30.99mA
-980mV    55.21mA    150.4mA    11.87mA
-920mV    21.5mA     109.2mA    1.195mA
-870mV    6.13mA     75.36mA    121.6uA
-820mV    1.189mA    45.7mA     11.82uA
-770mV    199.4uA    22.94mA    1.144uA
-730mV    46.68uA    11.1mA     176.6nA
-680mV    7.557uA    3.666mA    17.16nA
-510mV    15.46nA    46.13uA    134.2pA
2.4V      0A         0A         0A
[GND Clamp]
-1.2V     -616.6mA   -870.4mA   -486.7mA
-960mV    -208.6mA   -462.4mA   -78.75mA
-940mV    -174.6mA   -428.4mA   -56.97mA
-880mV    -73.49mA   -326.4mA   -34.53mA
-850mV    -45.28mA   -275.4mA   -29.09mA
-810mV    -29.66mA   -207.4mA   -23mA
-730mV    -17.09mA   -73.72mA   -13.06mA
-690mV    -13mA      -37.99mA   -9.157mA
-640mV    -8.81mA    -19.57mA   -5.341mA
-520mV    -2.385mA   -6.292mA   -748.7uA
-300mV    -8.501uA   -273.8uA   -150.7nA
2.4V      1.845nA    2.377uA    739.2pA
| variable   typ   min   max
[Pullup Reference] 1.2V 900.0mV 1.32V
| variable   typ   min   max
[Pulldown Reference] 0V 0V 0V
[Pullup]
-1.2V     523.2uA    222.6uA    755.5uA
-580mV    523.2uA    222.6uA    746.6uA
-490mV    510.3uA    222.6uA    638.2uA
-350mV    358uA      219.1uA    429.6uA
-200mV    186.4uA    122uA      224.9uA
-20mV     16.16uA    9.918uA    19.76uA
90mV      -65.82uA   -39.32uA   -80.52uA
200mV     -131.4uA   -76.44uA   -160.5uA
420mV     -215.5uA   -116.6uA   -262.7uA
540mV     -237.4uA   -123.5uA   -289.1uA
790mV     -252uA     -127.5uA   -307.1uA
2.4V      -265.4uA   -132.2uA   -325uA
[Pulldown]
-1.2V     -1.691mA   -757.3uA   -2.353mA
-760mV    -1.691mA   -757.3uA   -2.334mA
-580mV    -1.582mA   -757.3uA   -2.173mA
-430mV    -1.293mA   -666.6uA   -1.684mA
-200mV    -558.4uA   -310.3uA   -726.5uA
10mV      24.06uA    11.99uA    32.4uA
150mV     302.2uA    144.8uA    405.5uA
290mV     480.2uA    217.4uA    644uA
540mV     595.8uA    244.2uA    798.9uA
1.76V     653.9uA    285.4uA    807.9uA
2.11V     688.3uA    285.4uA    916.9uA
2.4V      688.3uA    285.4uA    918.5uA
[Ramp]
dV/dt_r 7.74232mV/11.76024ns 3.84613mV/21.11233ns 9.49137mV/9.12725ns
dV/dt_f 18.01342mV/12.12404ns 7.34723mV/20.45932ns 24.1393mV/9.98916ns
R_load = 50.0
| Removed startup time: 0s 0s 0s  .
| Removed end time: 48.4ns.
[Rising Waveform]
R_fixture   = 50.0
V_fixture   = 1.2V
V_fixture_min = 900.0mV
V_fixture_max = 1.32V
0s        1.17V      887.8mV    1.28V
7.5ns     1.17V      887.8mV    1.28V
7.9ns     1.17V      887.8mV    1.283V
9.8ns     1.17V      887.8mV    1.312V
11.75ns   1.19V      887.8mV    1.319V
12.85ns   1.196V     887.8mV    1.319V
15.55ns   1.199V     887.7mV    1.32V
19.75ns   1.2V       896.4mV    1.32V
22.75ns   1.2V       899.1mV    1.32V
48.4ns    1.2V       899.9mV    1.32V
| Removed startup time: 0s 0s 0s  .
| Removed end time: 198.4ns.
[Falling Waveform]
R_fixture   = 50.0
V_fixture   = 1.2V
V_fixture_min = 900.0mV
V_fixture_max = 1.32V
0s        1.2V       900mV      1.32V
24.45ns   1.2V       900mV      1.32V
25.9ns    1.2V       900mV      1.312V
28.65ns   1.2V       900mV      1.304V
33.4ns    1.188V     900mV      1.292V
39.5ns    1.179V     900mV      1.284V
46.05ns   1.174V     898.5mV    1.281V
64.8ns    1.17V      890.9mV    1.28V
81ns      1.17V      888.6mV    1.28V
198.4ns   1.17V      887.7mV    1.28V
| Removed startup time: 0s 0s 0s  .
| Removed end time: 198.35ns.
[Rising Waveform]
R_fixture   = 50.0
V_fixture   = 0V
V_fixture_min = 0V
V_fixture_max = 0V
0s        19.98nV    4.257uV    19.22nV
9.3ns     20.1uV     4.249uV    -675.7uV
18ns      -96.02uV   -262.6uV   665.6uV
21.35ns   135.1uV    -195.8uV   4.859mV
28.65ns   5.754mV    -19.91uV   12.37mV
34.05ns   9.274mV    154.9uV    14.59mV
41.1ns    11.59mV    1.063mV    15.62mV
58.8ns    12.85mV    4.595mV    15.83mV
73.95ns   12.9mV     5.908mV    15.82mV
198.3ns   12.9mV     6.414mV    15.82mV
| Removed startup time: 0s 0s 0s  .
| Removed end time: 68.4ns.
[Falling Waveform]
R_fixture   = 50.0
V_fixture   = 0V
V_fixture_min = 0V
V_fixture_max = 0V
0s        12.91mV    6.42mV     15.82mV
8.4ns     12.91mV    6.42mV     15.63mV
11.2ns    12.53mV    6.42mV     11.04mV
16ns      6.964mV    6.418mV    4.254mV
18.25ns   4.751mV    6.438mV    2.083mV
20.55ns   2.812mV    5.679mV    886.5uV
24.25ns   874.7uV    4.17mV     291.9uV
36.3ns    72.44uV    754.4uV    26.77uV
47.5ns    8.751uV    123.5uV    51.35nV
68.4ns    -479.1nV   18.88uV    -35.11nV
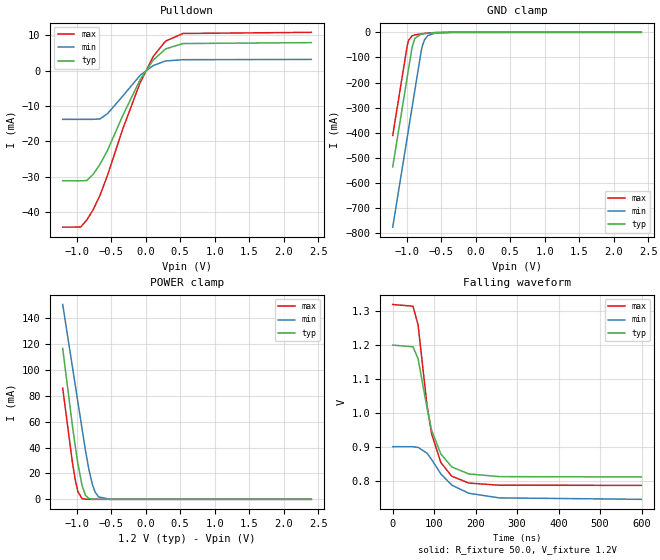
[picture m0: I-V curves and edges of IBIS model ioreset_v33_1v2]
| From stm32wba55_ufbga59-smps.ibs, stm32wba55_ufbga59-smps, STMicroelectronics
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[Model]   ioreset_v33_1v2
Model_type I/O_open_drain
Polarity   Inverting
Enable   Active-Low
| CAP_THRESHOLD on pad IOFT is "UDTCAPC" :
| Rising=30.0% of vddiom   Falling=70.0% of vddiom
| C_comp min and max val. don't necessarily correlate with the min and max pvt
| but are the smallest and greatest pad capacitance found.
| var   typ   min   max
C_comp   1.06069pF  952.65500fF  1.09790pF
|C_comp_pulldown   1.06069pF  952.65500fF  1.09790pF
Vinl = 450.0mV
Vinh = 660.0mV
Vmeas = 600.0mV   | Reference voltage for timing measurements
Cref  = 50.0pF   | Timing specification test load capacitance value
Rref  = 1.0MOhm   | Timing specification test load resistance value
Vref  = 660.0mV   | Timing specification test load voltage
[Model Spec]
| TIME_THRESHOLD on pin ZIV33M is "CMOS" :
| Rising=50.0% of vddiom   Falling=50.0% of vddiom
Vinl 439.50000mV 344.50000mV 469.50000mV
Vinh 749.50000mV 546.50000mV 836.50000mV
| variable   typ   min   max
[Temperature Range] 25.0 140.0 -40.0
| variable   typ   min   max
[Voltage Range] 1.2V 900.0mV 1.32V
| variable   typ   min   max
[POWER Clamp Reference] 1.2V 900.0mV 1.32V
| variable   typ   min   max
[GND Clamp Reference] 0V 0V 0V
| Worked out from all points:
|   slope of the pulldown table from 0 to 0.18 V, typ, clamps not added: 40.7 ohm
|   GND clamp passes 1 mA (typ) near -0.54 V on its own axis
|   POWER clamp passes 1 mA (typ) near -0.83 V on its own axis
|   falling waveform, R_fixture 50.0, V_fixture 1.2V: 20-80 % time 43.9ns typ, 66.7ns min, 37.7ns max; typ from 1.2 V to 0.81 V
[POWER Clamp]
-1.2V     116.7mA    150.7mA    85.92mA
-1.06V    57.23mA    102.6mA    28.68mA
-1.02V    41.75mA    88.91mA    15.5mA
-980mV    27.6mA     75.18mA    5.935mA
-920mV    10.75mA    54.6mA     597.6uA
-870mV    3.065mA    37.68mA    60.82uA
-820mV    594.6uA    22.85mA    5.912uA
-770mV    99.71uA    11.47mA    572nA
-730mV    23.34uA    5.553mA    88.28nA
-680mV    3.778uA    1.833mA    8.552nA
-510mV    7.733nA    23.38uA    27.92pA
2.4V      0A         0A         0A
[GND Clamp]
-1.2V     -535.9mA   -776mA     -410.9mA
-990mV    -178.9mA   -419mA     -53.87mA
-970mV    -144.9mA   -385mA     -31.62mA
-920mV    -59.9mA    -300mA     -14.15mA
-880mV    -24.1mA    -232mA     -10.55mA
-790mV    -7.719mA   -79.01mA   -6.216mA
-770mV    -6.703mA   -53.21mA   -5.437mA
-740mV    -5.508mA   -29.92mA   -4.362mA
-690mV    -3.935mA   -12.43mA   -2.832mA
-590mV    -1.686mA   -3.55mA    -843.5uA
-350mV    -13.34uA   -218.9uA   -428.1nA
2.4V      271.1pA    139.4nA    168.1pA
| variable   typ   min   max
[Pullup Reference] 1.2V 900.0mV 1.32V
| variable   typ   min   max
[Pulldown Reference] 0V 0V 0V
[Pulldown]
-1.2V     -31.18mA   -13.79mA   -44.28mA
-940mV    -31.18mA   -13.79mA   -44.24mA
-850mV    -31.09mA   -13.79mA   -42.24mA
-760mV    -29.36mA   -13.79mA   -39.35mA
-660mV    -26.5mA    -13.67mA   -35.28mA
-550mV    -22.52mA   -12.16mA   -29.56mA
-330mV    -12.72mA   -7.19mA    -16.47mA
-80mV     -2.616mA   -1.366mA   -3.483mA
110mV     2.955mA    1.423mA    3.99mA
290mV     6.125mA    2.725mA    8.323mA
540mV     7.644mA    3.08mA     10.49mA
2.4V      7.914mA    3.158mA    10.82mA
[Ramp]
dV/dt_r 228.47916mV/750.01786ps 92.86008mV/1.38879ns 321.68673mV/580.20405ps
dV/dt_f 233.72318mV/43.05346ns 93.27782mV/65.22479ns 320.57883mV/37.07664ns
R_load = 50.0
| Removed startup time: 0s 0s 0s  .
| Removed end time: 599.25ns.
[Falling Waveform]
R_fixture   = 50.0
V_fixture   = 1.2V
V_fixture_min = 900.0mV
V_fixture_max = 1.32V
0s        1.2V       900mV      1.32V
48.9ns    1.195V     899.9mV    1.315V
61.15ns   1.16V      897.9mV    1.26V
82.55ns   1.016V     880.8mV    1.024V
93.6ns    949mV      862.5mV    938.6mV
116.1ns   878.4mV    819.6mV    852.9mV
142.6ns   840mV      786.3mV    812.7mV
183.4ns   819.5mV    762.4mV    792.6mV
256.9ns   811.6mV    748.8mV    786.2mV
599.3ns   810.5mV    744.5mV    785.7mV
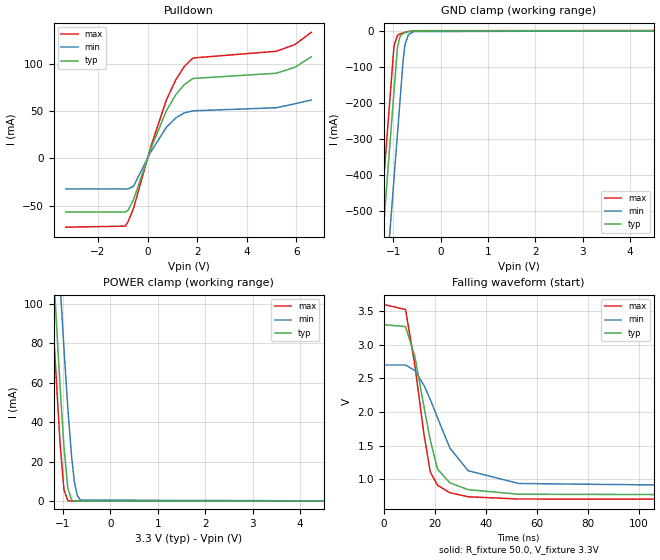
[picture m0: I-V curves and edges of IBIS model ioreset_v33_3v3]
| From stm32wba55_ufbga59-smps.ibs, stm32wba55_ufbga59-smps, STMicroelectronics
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[Model]   ioreset_v33_3v3
Model_type I/O_open_drain
Polarity   Inverting
Enable   Active-Low
| CAP_THRESHOLD on pad IOFT is "UDTCAPC" :
| Rising=30.0% of vddiom   Falling=70.0% of vddiom
| C_comp min and max val. don't necessarily correlate with the min and max pvt
| but are the smallest and greatest pad capacitance found.
| var   typ   min   max
C_comp   2.10660pF  1.66985pF  2.17235pF
|C_comp_pulldown   2.10660pF  1.66985pF  2.17235pF
Vinl = 1.35V
Vinh = 1.8V
Vmeas = 1.65V   | Reference voltage for timing measurements
Cref  = 50.0pF   | Timing specification test load capacitance value
Rref  = 1.0MOhm   | Timing specification test load resistance value
Vref  = 1.815V   | Timing specification test load voltage
[Model Spec]
| TIME_THRESHOLD on pin ZIV33M is "CMOS" :
| Rising=50.0% of vddiom   Falling=50.0% of vddiom
Vinl 1.28550V 1.07750V 1.38550V
Vinh 1.78850V 1.48350V 1.93520V
| variable   typ   min   max
[Temperature Range] 25.0 140.0 -40.0
| variable   typ   min   max
[Voltage Range] 3.3V 2.7V 3.6V
| variable   typ   min   max
[POWER Clamp Reference] 3.3V 2.7V 3.6V
| variable   typ   min   max
[GND Clamp Reference] 0V 0V 0V
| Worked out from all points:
|   slope of the pulldown table from 0 to 0.495 V, typ, clamps not added: 14 ohm
|   POWER clamp passes 1 mA (typ) near -0.83 V on its own axis
|   falling waveform, R_fixture 50.0, V_fixture 3.3V: 20-80 % time 7.66ns typ, 12.8ns min, 6.53ns max; typ from 3.3 V to 0.765 V
[POWER Clamp]
-3.3V     1.123A     1.139A     1.091A
-1.36V    189.2mA    238.8mA    158.1mA
-1.25V    139mA      190.3mA    108.1mA
-1.18V    107.9mA    159.9mA    77.22mA
-1.06V    57.23mA    109.3mA    28.68mA
-980mV    27.6mA     77.28mA    5.935mA
-900mV    6.895mA    47.74mA    242.8uA
-820mV    594.6uA    22.85mA    5.912uA
-760mV    69.41uA    9.714mA    358.6nA
-700mV    7.83uA     2.919mA    21.81nA
-630mV    611.2nA    530.3uA    910.5pA
6.6V      0A         0A         0A
[GND Clamp]
-3.3V     -4.107A    -4.349A    -3.982A
-1.59V    -1.2A      -1.442A    -1.075A
-1.25V    -622.5mA   -864.1mA   -496.7mA
-990mV    -180.5mA   -422.1mA   -54.66mA
-980mV    -163.5mA   -405.1mA   -41.45mA
-910mV    -48.31mA   -286.1mA   -13.42mA
-860mV    -17.65mA   -201.1mA   -9.771mA
-790mV    -8.222mA   -82.06mA   -6.465mA
-750mV    -6.254mA   -38.4mA    -4.889mA
-680mV    -3.875mA   -11.7mA    -2.654mA
-560mV    -1.264mA   -2.961mA   -523.3uA
6.6V      692.3pA    312.9nA    481.8pA
| variable   typ   min   max
[Pullup Reference] 3.3V 2.7V 3.6V
| variable   typ   min   max
[Pulldown Reference] 0V 0V 0V
[Pulldown]
-3.3V     -56.68mA   -32.38mA   -72.71mA
-900mV    -56.68mA   -32.38mA   -71.65mA
-800mV    -55.24mA   -32.38mA   -67.48mA
-570mV    -43.92mA   -29.53mA   -52.95mA
120mV     9.466mA    6.4mA      11.47mA
760mV     50.45mA    32.88mA    61.77mA
1.14V     67.34mA    42.68mA    83.12mA
1.48V     77.88mA    47.94mA    96.93mA
1.83V     84.28mA    50.12mA    105.9mA
5.19V     89.8mA     53.35mA    113mA
5.94V     96.11mA    57.57mA    120.1mA
6.6V      107.2mA    61.53mA    133mA
[Ramp]
dV/dt_r 1.53826V/219.24583ps 1.09873V/311.83722ps 1.73124V/189.17048ps
dV/dt_f 1.52116V/7.65523ns 1.0926V/12.79534ns 1.73878V/6.2384ns
R_load = 50.0
| Removed startup time: 0s 0s 0s  .
| Removed end time: 199.25ns.
[Falling Waveform]
R_fixture   = 50.0
V_fixture   = 3.3V
V_fixture_min = 2.7V
V_fixture_max = 3.6V
0s        3.3V       2.7V       3.6V
8.55ns    3.271V     2.7V       3.526V
12.2ns    2.825V     2.617V     2.7V
15.75ns   2.084V     2.399V     1.673V
18.25ns   1.581V     2.186V     1.107V
21.1ns    1.15V      1.914V     911.5mV
25.9ns    947.7mV    1.466V     800.8mV
33.05ns   846.1mV    1.128V     740.1mV
52.9ns    777.7mV    937.3mV    706.5mV
199.3ns   764.7mV    879mV      701.9mV
